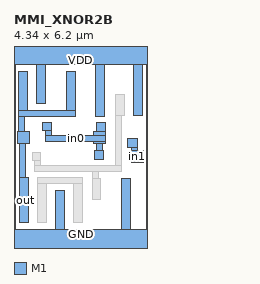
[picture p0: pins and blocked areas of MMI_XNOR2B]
MACRO MMI_XNOR2B
	CLASS CORE ;
	FOREIGN MMI_XNOR2B 0 0 ;
	SIZE 4.34 BY 6.2 ;
	SYMMETRY X Y ;
	SITE CORE1 ;
	PIN out
		DIRECTION output ;
		USE SIGNAL ;
		PORT
			LAYER M1 ;
			RECT 0.16 4.3 0.44 5.58 ;
			LAYER M1 ;
			RECT 1.715 4.3 1.995 5.58 ;
			LAYER M1 ;
			RECT 0.16 4.11 1.995 4.3 ;
			LAYER M1 ;
			RECT 0.16 3.6 0.355 4.11 ;
			LAYER M1 ;
			RECT 0.12 3.22 0.5 3.6 ;
			LAYER M1 ;
			RECT 0.185 2.095 0.38 3.22 ;
			LAYER M1 ;
			RECT 0.185 0.625 0.465 2.095 ;
		END
		AntennaDiffArea 1.8942 ;
	END out
	PIN in1
		DIRECTION input ;
		USE SIGNAL ;
		PORT
			LAYER M1 ;
			RECT 3.71 3.1 4.035 3.38 ;
			LAYER M1 ;
			RECT 3.84 2.98 4.035 3.1 ;
			LAYER M1 ;
			RECT 3.84 2.6 4.22 2.98 ;
		END
		AntennaGateArea 0.924 ;
	END in1
	PIN GND
		DIRECTION inout ;
		USE GROUND ;
		PORT
			LAYER M1 ;
			RECT 1.365 0.42 1.645 1.685 ;
			LAYER M1 ;
			RECT 3.515 0.42 3.795 2.085 ;
			LAYER M1 ;
			RECT 0 -0.42 4.34 0.42 ;
		END
	END GND
	PIN VDD
		DIRECTION inout ;
		USE POWER ;
		PORT
			LAYER M1 ;
			RECT 0 5.78 4.34 6.62 ;
			LAYER M1 ;
			RECT 0.75 4.52 1.03 5.78 ;
			LAYER M1 ;
			RECT 2.675 4.11 2.955 5.78 ;
			LAYER M1 ;
			RECT 3.905 4.115 4.185 5.78 ;
		END
	END VDD
	PIN in0
		DIRECTION input ;
		USE SIGNAL ;
		PORT
			LAYER M1 ;
			RECT 0.945 3.63 1.225 3.91 ;
			LAYER M1 ;
			RECT 1.035 3.465 1.225 3.63 ;
			LAYER M1 ;
			RECT 2.69 3.6 2.97 3.91 ;
			LAYER M1 ;
			RECT 2.6 3.465 2.98 3.6 ;
			LAYER M1 ;
			RECT 1.035 3.27 2.98 3.465 ;
			LAYER M1 ;
			RECT 2.6 3.22 2.98 3.27 ;
			LAYER M1 ;
			RECT 2.705 2.97 2.9 3.22 ;
			LAYER M1 ;
			RECT 2.64 2.69 2.92 2.97 ;
		END
		AntennaGateArea 0.924 ;
	END in0
	OBS
		LAYER M1 ;
		RECT 3.315 4.115 3.595 4.815 ;
		LAYER M1 ;
		RECT 0.59 2.65 0.87 2.93 ;
		LAYER M1 ;
		RECT 0.68 2.49 0.87 2.65 ;
		LAYER M1 ;
		RECT 3.315 2.49 3.505 4.115 ;
		LAYER M1 ;
		RECT 0.68 2.295 3.505 2.49 ;
		LAYER M1 ;
		RECT 0.775 1.905 2.235 2.095 ;
		LAYER M1 ;
		RECT 0.775 0.625 1.055 1.905 ;
		LAYER M1 ;
		RECT 1.955 0.625 2.235 1.905 ;
		LAYER M1 ;
		RECT 2.555 2.085 2.745 2.295 ;
		LAYER M1 ;
		RECT 2.555 1.385 2.835 2.085 ;
	END
END MMI_XNOR2B
